VERSION 5.7 ;
  NOWIREEXTENSIONATPIN ON ;
  DIVIDERCHAR "/" ;
  BUSBITCHARS "[]" ;
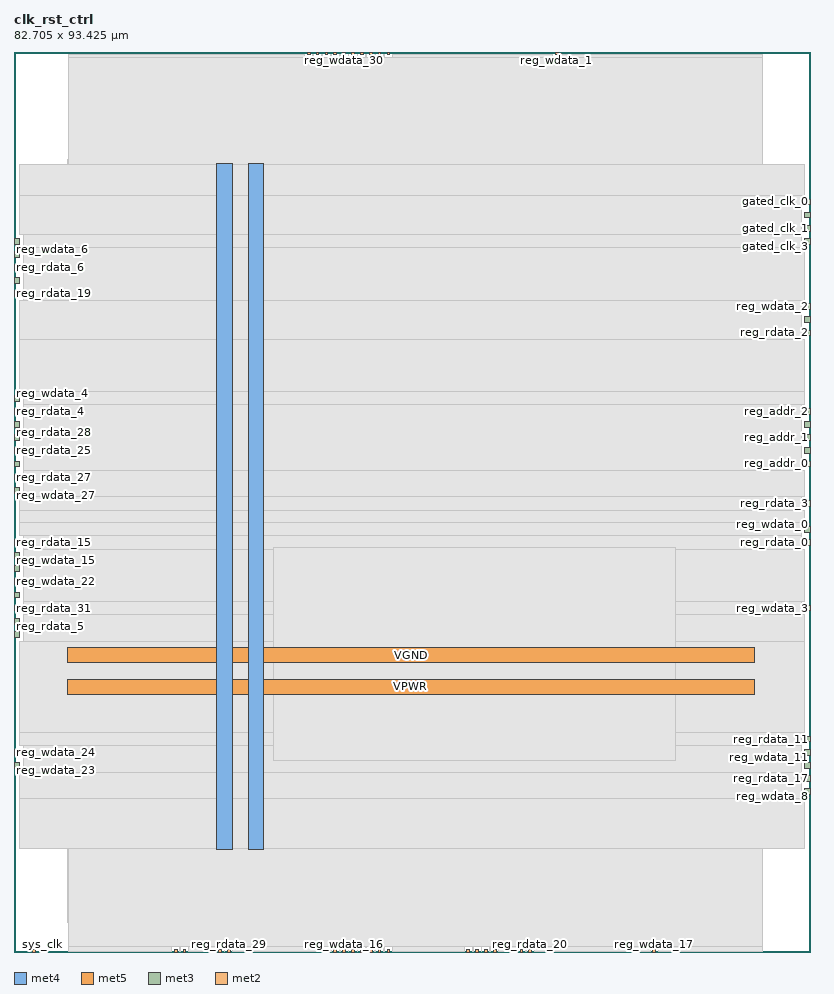
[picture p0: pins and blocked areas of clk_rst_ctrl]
MACRO clk_rst_ctrl
  CLASS BLOCK ;
  FOREIGN clk_rst_ctrl ;
  ORIGIN 0.000 0.000 ;
  SIZE 82.705 BY 93.425 ;
  PIN VGND
    DIRECTION INOUT ;
    USE GROUND ;
    PORT
      LAYER met4 ;
        RECT 24.340 10.640 25.940 81.840 ;
    END
    PORT
      LAYER met5 ;
        RECT 5.520 30.030 76.820 31.630 ;
    END
  END VGND
  PIN VPWR
    DIRECTION INOUT ;
    USE POWER ;
    PORT
      LAYER met4 ;
        RECT 21.040 10.640 22.640 81.840 ;
    END
    PORT
      LAYER met5 ;
        RECT 5.520 26.730 76.820 28.330 ;
    END
  END VPWR
  PIN gated_clk_0
    DIRECTION OUTPUT ;
    USE SIGNAL ;
    ANTENNAGATEAREA 0.434700 ;
    ANTENNADIFFAREA 0.434700 ;
    PORT
      LAYER met3 ;
        RECT 82.105 77.560 82.705 78.160 ;
    END
  END gated_clk_0
  PIN gated_clk_1
    DIRECTION OUTPUT ;
    USE SIGNAL ;
    ANTENNAGATEAREA 0.434700 ;
    ANTENNADIFFAREA 0.775300 ;
    PORT
      LAYER met3 ;
        RECT 82.105 74.840 82.705 75.440 ;
    END
  END gated_clk_1
  PIN gated_clk_2
    DIRECTION OUTPUT ;
    USE SIGNAL ;
    ANTENNAGATEAREA 0.434700 ;
    ANTENNADIFFAREA 0.775300 ;
    PORT
      LAYER met3 ;
        RECT 82.105 76.200 82.705 76.800 ;
    END
  END gated_clk_2
  PIN gated_clk_3
    DIRECTION OUTPUT ;
    USE SIGNAL ;
    ANTENNAGATEAREA 0.434700 ;
    ANTENNADIFFAREA 0.775300 ;
    PORT
      LAYER met3 ;
        RECT 82.105 73.480 82.705 74.080 ;
    END
  END gated_clk_3
  PIN reg_addr_0
    DIRECTION INPUT ;
    USE SIGNAL ;
    ANTENNAGATEAREA 0.647700 ;
    ANTENNADIFFAREA 0.434700 ;
    PORT
      LAYER met3 ;
        RECT 82.105 50.360 82.705 50.960 ;
    END
  END reg_addr_0
  PIN reg_addr_1
    DIRECTION INPUT ;
    USE SIGNAL ;
    ANTENNAGATEAREA 0.647700 ;
    ANTENNADIFFAREA 0.434700 ;
    PORT
      LAYER met3 ;
        RECT 82.105 53.080 82.705 53.680 ;
    END
  END reg_addr_1
  PIN reg_addr_2
    DIRECTION INPUT ;
    USE SIGNAL ;
    ANTENNAGATEAREA 0.647700 ;
    ANTENNADIFFAREA 0.434700 ;
    PORT
      LAYER met3 ;
        RECT 82.105 55.800 82.705 56.400 ;
    END
  END reg_addr_2
  PIN reg_addr_3
    DIRECTION INPUT ;
    USE SIGNAL ;
    ANTENNAGATEAREA 0.647700 ;
    ANTENNADIFFAREA 0.434700 ;
    PORT
      LAYER met3 ;
        RECT 82.105 51.720 82.705 52.320 ;
    END
  END reg_addr_3
  PIN reg_rd
    DIRECTION INPUT ;
    USE SIGNAL ;
    PORT
      LAYER met2 ;
        RECT 1.930 0.000 2.210 0.280 ;
    END
  END reg_rd
  PIN reg_rdata_0
    DIRECTION OUTPUT ;
    USE SIGNAL ;
    ANTENNAGATEAREA 0.434700 ;
    ANTENNADIFFAREA 1.137600 ;
    PORT
      LAYER met3 ;
        RECT 82.105 42.200 82.705 42.800 ;
    END
  END reg_rdata_0
  PIN reg_rdata_1
    DIRECTION OUTPUT ;
    USE SIGNAL ;
    ANTENNAGATEAREA 0.434700 ;
    ANTENNADIFFAREA 1.137600 ;
    PORT
      LAYER met3 ;
        RECT 82.105 65.320 82.705 65.920 ;
    END
  END reg_rdata_1
  PIN reg_rdata_10
    DIRECTION OUTPUT ;
    USE SIGNAL ;
    ANTENNAGATEAREA 0.434700 ;
    ANTENNADIFFAREA 1.137600 ;
    PORT
      LAYER met2 ;
        RECT 38.730 0.000 39.010 0.280 ;
    END
  END reg_rdata_10
  PIN reg_rdata_11
    DIRECTION OUTPUT ;
    USE SIGNAL ;
    ANTENNAGATEAREA 0.434700 ;
    ANTENNADIFFAREA 1.137600 ;
    PORT
      LAYER met3 ;
        RECT 82.105 21.800 82.705 22.400 ;
    END
  END reg_rdata_11
  PIN reg_rdata_12
    DIRECTION OUTPUT ;
    USE SIGNAL ;
    ANTENNAGATEAREA 0.434700 ;
    ANTENNADIFFAREA 1.137600 ;
    PORT
      LAYER met2 ;
        RECT 32.290 0.000 32.570 0.280 ;
    END
  END reg_rdata_12
  PIN reg_rdata_13
    DIRECTION OUTPUT ;
    USE SIGNAL ;
    ANTENNAGATEAREA 0.434700 ;
    ANTENNADIFFAREA 1.137600 ;
    PORT
      LAYER met2 ;
        RECT 31.370 93.145 31.650 93.425 ;
    END
  END reg_rdata_13
  PIN reg_rdata_14
    DIRECTION OUTPUT ;
    USE SIGNAL ;
    ANTENNAGATEAREA 0.434700 ;
    ANTENNADIFFAREA 1.137600 ;
    PORT
      LAYER met2 ;
        RECT 33.210 93.145 33.490 93.425 ;
    END
  END reg_rdata_14
  PIN reg_rdata_15
    DIRECTION OUTPUT ;
    USE SIGNAL ;
    ANTENNAGATEAREA 0.434700 ;
    ANTENNADIFFAREA 1.137600 ;
    PORT
      LAYER met3 ;
        RECT 0.000 42.200 0.600 42.800 ;
    END
  END reg_rdata_15
  PIN reg_rdata_16
    DIRECTION OUTPUT ;
    USE SIGNAL ;
    ANTENNAGATEAREA 0.434700 ;
    ANTENNADIFFAREA 1.137600 ;
    PORT
      LAYER met2 ;
        RECT 35.970 0.000 36.250 0.280 ;
    END
  END reg_rdata_16
  PIN reg_rdata_17
    DIRECTION OUTPUT ;
    USE SIGNAL ;
    ANTENNAGATEAREA 0.434700 ;
    ANTENNADIFFAREA 1.137600 ;
    PORT
      LAYER met3 ;
        RECT 82.105 17.720 82.705 18.320 ;
    END
  END reg_rdata_17
  PIN reg_rdata_18
    DIRECTION OUTPUT ;
    USE SIGNAL ;
    ANTENNAGATEAREA 0.434700 ;
    ANTENNADIFFAREA 1.137600 ;
    PORT
      LAYER met2 ;
        RECT 38.730 93.145 39.010 93.425 ;
    END
  END reg_rdata_18
  PIN reg_rdata_19
    DIRECTION OUTPUT ;
    USE SIGNAL ;
    ANTENNAGATEAREA 0.434700 ;
    ANTENNADIFFAREA 1.137600 ;
    PORT
      LAYER met3 ;
        RECT 0.000 68.040 0.600 68.640 ;
    END
  END reg_rdata_19
  PIN reg_rdata_2
    DIRECTION OUTPUT ;
    USE SIGNAL ;
    ANTENNAGATEAREA 0.434700 ;
    ANTENNADIFFAREA 1.137600 ;
    PORT
      LAYER met3 ;
        RECT 82.105 63.960 82.705 64.560 ;
    END
  END reg_rdata_2
  PIN reg_rdata_20
    DIRECTION OUTPUT ;
    USE SIGNAL ;
    ANTENNAGATEAREA 0.434700 ;
    ANTENNADIFFAREA 1.137600 ;
    PORT
      LAYER met2 ;
        RECT 53.450 0.000 53.730 0.280 ;
    END
  END reg_rdata_20
  PIN reg_rdata_21
    DIRECTION OUTPUT ;
    USE SIGNAL ;
    ANTENNAGATEAREA 0.434700 ;
    ANTENNADIFFAREA 1.137600 ;
    PORT
      LAYER met2 ;
        RECT 36.890 93.145 37.170 93.425 ;
    END
  END reg_rdata_21
  PIN reg_rdata_22
    DIRECTION OUTPUT ;
    USE SIGNAL ;
    ANTENNAGATEAREA 0.434700 ;
    ANTENNADIFFAREA 1.137600 ;
    PORT
      LAYER met3 ;
        RECT 0.000 39.480 0.600 40.080 ;
    END
  END reg_rdata_22
  PIN reg_rdata_23
    DIRECTION OUTPUT ;
    USE SIGNAL ;
    ANTENNAGATEAREA 0.434700 ;
    ANTENNADIFFAREA 1.137600 ;
    PORT
      LAYER met2 ;
        RECT 17.570 0.000 17.850 0.280 ;
    END
  END reg_rdata_23
  PIN reg_rdata_24
    DIRECTION OUTPUT ;
    USE SIGNAL ;
    ANTENNAGATEAREA 0.434700 ;
    ANTENNADIFFAREA 1.137600 ;
    PORT
      LAYER met2 ;
        RECT 16.650 0.000 16.930 0.280 ;
    END
  END reg_rdata_24
  PIN reg_rdata_25
    DIRECTION OUTPUT ;
    USE SIGNAL ;
    ANTENNAGATEAREA 0.434700 ;
    ANTENNADIFFAREA 1.137600 ;
    PORT
      LAYER met3 ;
        RECT 0.000 51.720 0.600 52.320 ;
    END
  END reg_rdata_25
  PIN reg_rdata_26
    DIRECTION OUTPUT ;
    USE SIGNAL ;
    ANTENNAGATEAREA 0.434700 ;
    ANTENNADIFFAREA 1.137600 ;
    PORT
      LAYER met2 ;
        RECT 49.770 0.000 50.050 0.280 ;
    END
  END reg_rdata_26
  PIN reg_rdata_27
    DIRECTION OUTPUT ;
    USE SIGNAL ;
    ANTENNAGATEAREA 0.434700 ;
    ANTENNADIFFAREA 1.137600 ;
    PORT
      LAYER met3 ;
        RECT 0.000 49.000 0.600 49.600 ;
    END
  END reg_rdata_27
  PIN reg_rdata_28
    DIRECTION OUTPUT ;
    USE SIGNAL ;
    ANTENNAGATEAREA 0.434700 ;
    ANTENNADIFFAREA 1.137600 ;
    PORT
      LAYER met3 ;
        RECT 0.000 53.080 0.600 53.680 ;
    END
  END reg_rdata_28
  PIN reg_rdata_29
    DIRECTION OUTPUT ;
    USE SIGNAL ;
    ANTENNAGATEAREA 0.434700 ;
    ANTENNADIFFAREA 1.137600 ;
    PORT
      LAYER met2 ;
        RECT 22.170 0.000 22.450 0.280 ;
    END
  END reg_rdata_29
  PIN reg_rdata_3
    DIRECTION OUTPUT ;
    USE SIGNAL ;
    ANTENNAGATEAREA 0.434700 ;
    ANTENNADIFFAREA 1.137600 ;
    PORT
      LAYER met3 ;
        RECT 82.105 46.280 82.705 46.880 ;
    END
  END reg_rdata_3
  PIN reg_rdata_30
    DIRECTION OUTPUT ;
    USE SIGNAL ;
    ANTENNAGATEAREA 0.434700 ;
    ANTENNADIFFAREA 1.137600 ;
    PORT
      LAYER met2 ;
        RECT 35.970 93.145 36.250 93.425 ;
    END
  END reg_rdata_30
  PIN reg_rdata_31
    DIRECTION OUTPUT ;
    USE SIGNAL ;
    ANTENNAGATEAREA 0.434700 ;
    ANTENNADIFFAREA 1.137600 ;
    PORT
      LAYER met3 ;
        RECT 0.000 35.400 0.600 36.000 ;
    END
  END reg_rdata_31
  PIN reg_rdata_4
    DIRECTION OUTPUT ;
    USE SIGNAL ;
    ANTENNAGATEAREA 0.434700 ;
    ANTENNADIFFAREA 1.137600 ;
    PORT
      LAYER met3 ;
        RECT 0.000 55.800 0.600 56.400 ;
    END
  END reg_rdata_4
  PIN reg_rdata_5
    DIRECTION OUTPUT ;
    USE SIGNAL ;
    ANTENNAGATEAREA 0.434700 ;
    ANTENNADIFFAREA 1.137600 ;
    PORT
      LAYER met3 ;
        RECT 0.000 34.040 0.600 34.640 ;
    END
  END reg_rdata_5
  PIN reg_rdata_6
    DIRECTION OUTPUT ;
    USE SIGNAL ;
    ANTENNAGATEAREA 0.434700 ;
    ANTENNADIFFAREA 1.137600 ;
    PORT
      LAYER met3 ;
        RECT 0.000 70.760 0.600 71.360 ;
    END
  END reg_rdata_6
  PIN reg_rdata_7
    DIRECTION OUTPUT ;
    USE SIGNAL ;
    ANTENNAGATEAREA 0.434700 ;
    ANTENNADIFFAREA 1.137600 ;
    PORT
      LAYER met2 ;
        RECT 47.930 0.000 48.210 0.280 ;
    END
  END reg_rdata_7
  PIN reg_rdata_8
    DIRECTION OUTPUT ;
    USE SIGNAL ;
    ANTENNAGATEAREA 0.434700 ;
    ANTENNADIFFAREA 1.137600 ;
    PORT
      LAYER met3 ;
        RECT 82.105 19.080 82.705 19.680 ;
    END
  END reg_rdata_8
  PIN reg_rdata_9
    DIRECTION OUTPUT ;
    USE SIGNAL ;
    ANTENNAGATEAREA 0.434700 ;
    ANTENNADIFFAREA 1.137600 ;
    PORT
      LAYER met2 ;
        RECT 37.810 0.000 38.090 0.280 ;
    END
  END reg_rdata_9
  PIN reg_wdata_0
    DIRECTION INPUT ;
    USE SIGNAL ;
    ANTENNAGATEAREA 0.647700 ;
    ANTENNADIFFAREA 0.434700 ;
    PORT
      LAYER met3 ;
        RECT 82.105 43.560 82.705 44.160 ;
    END
  END reg_wdata_0
  PIN reg_wdata_1
    DIRECTION INPUT ;
    USE SIGNAL ;
    ANTENNAGATEAREA 0.647700 ;
    ANTENNADIFFAREA 0.434700 ;
    PORT
      LAYER met2 ;
        RECT 56.210 93.145 56.490 93.425 ;
    END
  END reg_wdata_1
  PIN reg_wdata_10
    DIRECTION INPUT ;
    USE SIGNAL ;
    ANTENNAGATEAREA 0.647700 ;
    ANTENNADIFFAREA 0.434700 ;
    PORT
      LAYER met2 ;
        RECT 35.050 0.000 35.330 0.280 ;
    END
  END reg_wdata_10
  PIN reg_wdata_11
    DIRECTION INPUT ;
    USE SIGNAL ;
    ANTENNAGATEAREA 0.647700 ;
    ANTENNADIFFAREA 0.434700 ;
    PORT
      LAYER met3 ;
        RECT 82.105 20.440 82.705 21.040 ;
    END
  END reg_wdata_11
  PIN reg_wdata_12
    DIRECTION INPUT ;
    USE SIGNAL ;
    ANTENNAGATEAREA 0.647700 ;
    ANTENNADIFFAREA 0.434700 ;
    PORT
      LAYER met2 ;
        RECT 33.210 0.000 33.490 0.280 ;
    END
  END reg_wdata_12
  PIN reg_wdata_13
    DIRECTION INPUT ;
    USE SIGNAL ;
    ANTENNAGATEAREA 0.647700 ;
    ANTENNADIFFAREA 0.434700 ;
    PORT
      LAYER met2 ;
        RECT 30.450 93.145 30.730 93.425 ;
    END
  END reg_wdata_13
  PIN reg_wdata_14
    DIRECTION INPUT ;
    USE SIGNAL ;
    ANTENNAGATEAREA 0.647700 ;
    ANTENNADIFFAREA 0.434700 ;
    PORT
      LAYER met2 ;
        RECT 32.290 93.145 32.570 93.425 ;
    END
  END reg_wdata_14
  PIN reg_wdata_15
    DIRECTION INPUT ;
    USE SIGNAL ;
    ANTENNAGATEAREA 0.647700 ;
    ANTENNADIFFAREA 0.434700 ;
    PORT
      LAYER met3 ;
        RECT 0.000 40.840 0.600 41.440 ;
    END
  END reg_wdata_15
  PIN reg_wdata_16
    DIRECTION INPUT ;
    USE SIGNAL ;
    ANTENNAGATEAREA 0.647700 ;
    ANTENNADIFFAREA 0.434700 ;
    PORT
      LAYER met2 ;
        RECT 34.130 0.000 34.410 0.280 ;
    END
  END reg_wdata_16
  PIN reg_wdata_17
    DIRECTION INPUT ;
    USE SIGNAL ;
    ANTENNAGATEAREA 0.647700 ;
    ANTENNADIFFAREA 0.434700 ;
    PORT
      LAYER met2 ;
        RECT 66.330 0.000 66.610 0.280 ;
    END
  END reg_wdata_17
  PIN reg_wdata_18
    DIRECTION INPUT ;
    USE SIGNAL ;
    ANTENNAGATEAREA 0.647700 ;
    ANTENNADIFFAREA 0.434700 ;
    PORT
      LAYER met2 ;
        RECT 37.810 93.145 38.090 93.425 ;
    END
  END reg_wdata_18
  PIN reg_wdata_19
    DIRECTION INPUT ;
    USE SIGNAL ;
    ANTENNAGATEAREA 0.647700 ;
    ANTENNADIFFAREA 0.434700 ;
    PORT
      LAYER met3 ;
        RECT 0.000 69.400 0.600 70.000 ;
    END
  END reg_wdata_19
  PIN reg_wdata_2
    DIRECTION INPUT ;
    USE SIGNAL ;
    ANTENNAGATEAREA 0.647700 ;
    ANTENNADIFFAREA 0.434700 ;
    PORT
      LAYER met3 ;
        RECT 82.105 66.680 82.705 67.280 ;
    END
  END reg_wdata_2
  PIN reg_wdata_20
    DIRECTION INPUT ;
    USE SIGNAL ;
    ANTENNAGATEAREA 0.647700 ;
    ANTENNADIFFAREA 0.434700 ;
    PORT
      LAYER met2 ;
        RECT 52.530 0.000 52.810 0.280 ;
    END
  END reg_wdata_20
  PIN reg_wdata_21
    DIRECTION INPUT ;
    USE SIGNAL ;
    ANTENNAGATEAREA 0.647700 ;
    ANTENNADIFFAREA 0.434700 ;
    PORT
      LAYER met2 ;
        RECT 35.050 93.145 35.330 93.425 ;
    END
  END reg_wdata_21
  PIN reg_wdata_22
    DIRECTION INPUT ;
    USE SIGNAL ;
    ANTENNAGATEAREA 0.647700 ;
    ANTENNADIFFAREA 0.434700 ;
    PORT
      LAYER met3 ;
        RECT 0.000 38.120 0.600 38.720 ;
    END
  END reg_wdata_22
  PIN reg_wdata_23
    DIRECTION INPUT ;
    USE SIGNAL ;
    ANTENNAGATEAREA 0.647700 ;
    ANTENNADIFFAREA 0.434700 ;
    PORT
      LAYER met3 ;
        RECT 0.000 19.080 0.600 19.680 ;
    END
  END reg_wdata_23
  PIN reg_wdata_24
    DIRECTION INPUT ;
    USE SIGNAL ;
    ANTENNAGATEAREA 0.647700 ;
    ANTENNADIFFAREA 0.434700 ;
    PORT
      LAYER met3 ;
        RECT 0.000 20.440 0.600 21.040 ;
    END
  END reg_wdata_24
  PIN reg_wdata_25
    DIRECTION INPUT ;
    USE SIGNAL ;
    ANTENNAGATEAREA 0.647700 ;
    ANTENNADIFFAREA 0.434700 ;
    PORT
      LAYER met3 ;
        RECT 0.000 50.360 0.600 50.960 ;
    END
  END reg_wdata_25
  PIN reg_wdata_26
    DIRECTION INPUT ;
    USE SIGNAL ;
    ANTENNAGATEAREA 0.647700 ;
    ANTENNADIFFAREA 0.434700 ;
    PORT
      LAYER met2 ;
        RECT 48.850 0.000 49.130 0.280 ;
    END
  END reg_wdata_26
  PIN reg_wdata_27
    DIRECTION INPUT ;
    USE SIGNAL ;
    ANTENNAGATEAREA 0.647700 ;
    ANTENNADIFFAREA 0.434700 ;
    PORT
      LAYER met3 ;
        RECT 0.000 47.640 0.600 48.240 ;
    END
  END reg_wdata_27
  PIN reg_wdata_28
    DIRECTION INPUT ;
    USE SIGNAL ;
    ANTENNAGATEAREA 0.647700 ;
    ANTENNADIFFAREA 0.434700 ;
    PORT
      LAYER met3 ;
        RECT 0.000 54.440 0.600 55.040 ;
    END
  END reg_wdata_28
  PIN reg_wdata_29
    DIRECTION INPUT ;
    USE SIGNAL ;
    ANTENNAGATEAREA 0.647700 ;
    ANTENNADIFFAREA 0.434700 ;
    PORT
      LAYER met2 ;
        RECT 21.250 0.000 21.530 0.280 ;
    END
  END reg_wdata_29
  PIN reg_wdata_3
    DIRECTION INPUT ;
    USE SIGNAL ;
    ANTENNAGATEAREA 0.647700 ;
    ANTENNADIFFAREA 0.434700 ;
    PORT
      LAYER met3 ;
        RECT 82.105 35.400 82.705 36.000 ;
    END
  END reg_wdata_3
  PIN reg_wdata_30
    DIRECTION INPUT ;
    USE SIGNAL ;
    ANTENNAGATEAREA 0.647700 ;
    ANTENNADIFFAREA 0.434700 ;
    PORT
      LAYER met2 ;
        RECT 34.130 93.145 34.410 93.425 ;
    END
  END reg_wdata_30
  PIN reg_wdata_31
    DIRECTION INPUT ;
    USE SIGNAL ;
    ANTENNAGATEAREA 0.647700 ;
    ANTENNADIFFAREA 0.434700 ;
    PORT
      LAYER met3 ;
        RECT 0.000 36.760 0.600 37.360 ;
    END
  END reg_wdata_31
  PIN reg_wdata_4
    DIRECTION INPUT ;
    USE SIGNAL ;
    ANTENNAGATEAREA 0.647700 ;
    ANTENNADIFFAREA 0.434700 ;
    PORT
      LAYER met3 ;
        RECT 0.000 57.160 0.600 57.760 ;
    END
  END reg_wdata_4
  PIN reg_wdata_5
    DIRECTION INPUT ;
    USE SIGNAL ;
    ANTENNAGATEAREA 0.647700 ;
    ANTENNADIFFAREA 0.434700 ;
    PORT
      LAYER met3 ;
        RECT 0.000 32.680 0.600 33.280 ;
    END
  END reg_wdata_5
  PIN reg_wdata_6
    DIRECTION INPUT ;
    USE SIGNAL ;
    ANTENNAGATEAREA 0.647700 ;
    ANTENNADIFFAREA 0.434700 ;
    PORT
      LAYER met3 ;
        RECT 0.000 72.120 0.600 72.720 ;
    END
  END reg_wdata_6
  PIN reg_wdata_7
    DIRECTION INPUT ;
    USE SIGNAL ;
    ANTENNAGATEAREA 0.647700 ;
    ANTENNADIFFAREA 0.434700 ;
    PORT
      LAYER met2 ;
        RECT 47.010 0.000 47.290 0.280 ;
    END
  END reg_wdata_7
  PIN reg_wdata_8
    DIRECTION INPUT ;
    USE SIGNAL ;
    ANTENNAGATEAREA 0.647700 ;
    ANTENNADIFFAREA 0.434700 ;
    PORT
      LAYER met3 ;
        RECT 82.105 16.360 82.705 16.960 ;
    END
  END reg_wdata_8
  PIN reg_wdata_9
    DIRECTION INPUT ;
    USE SIGNAL ;
    ANTENNAGATEAREA 0.647700 ;
    ANTENNADIFFAREA 0.434700 ;
    PORT
      LAYER met2 ;
        RECT 36.890 0.000 37.170 0.280 ;
    END
  END reg_wdata_9
  PIN reg_wr
    DIRECTION INPUT ;
    USE SIGNAL ;
    ANTENNAGATEAREA 0.647700 ;
    ANTENNADIFFAREA 0.434700 ;
    PORT
      LAYER met3 ;
        RECT 82.105 54.440 82.705 55.040 ;
    END
  END reg_wr
  PIN sys_clk
    DIRECTION OUTPUT ;
    USE SIGNAL ;
    PORT
      LAYER met2 ;
        RECT 2.850 0.000 3.130 0.280 ;
    END
  END sys_clk
  PIN sys_rst_n
    DIRECTION OUTPUT ;
    USE SIGNAL ;
    ANTENNAGATEAREA 0.434700 ;
    ANTENNADIFFAREA 1.137600 ;
    PORT
      LAYER met3 ;
        RECT 0.000 73.480 0.600 74.080 ;
    END
  END sys_rst_n
  OBS
      LAYER nwell ;
        RECT 5.330 10.795 77.010 81.685 ;
      LAYER li1 ;
        RECT 5.520 10.795 76.820 81.685 ;
      LAYER met1 ;
        RECT 5.520 3.100 77.670 82.240 ;
      LAYER met2 ;
        RECT 5.610 92.865 30.170 93.145 ;
        RECT 31.010 92.865 31.090 93.145 ;
        RECT 31.930 92.865 32.010 93.145 ;
        RECT 32.850 92.865 32.930 93.145 ;
        RECT 33.770 92.865 33.850 93.145 ;
        RECT 34.690 92.865 34.770 93.145 ;
        RECT 35.610 92.865 35.690 93.145 ;
        RECT 36.530 92.865 36.610 93.145 ;
        RECT 37.450 92.865 37.530 93.145 ;
        RECT 38.370 92.865 38.450 93.145 ;
        RECT 39.290 92.865 55.930 93.145 ;
        RECT 56.770 92.865 77.650 93.145 ;
        RECT 5.610 0.560 77.650 92.865 ;
        RECT 5.610 0.070 16.370 0.560 ;
        RECT 17.210 0.070 17.290 0.560 ;
        RECT 18.130 0.070 20.970 0.560 ;
        RECT 21.810 0.070 21.890 0.560 ;
        RECT 22.730 0.070 32.010 0.560 ;
        RECT 32.850 0.070 32.930 0.560 ;
        RECT 33.770 0.070 33.850 0.560 ;
        RECT 34.690 0.070 34.770 0.560 ;
        RECT 35.610 0.070 35.690 0.560 ;
        RECT 36.530 0.070 36.610 0.560 ;
        RECT 37.450 0.070 37.530 0.560 ;
        RECT 38.370 0.070 38.450 0.560 ;
        RECT 39.290 0.070 46.730 0.560 ;
        RECT 47.570 0.070 47.650 0.560 ;
        RECT 48.490 0.070 48.570 0.560 ;
        RECT 49.410 0.070 49.490 0.560 ;
        RECT 50.330 0.070 52.250 0.560 ;
        RECT 53.090 0.070 53.170 0.560 ;
        RECT 54.010 0.070 66.050 0.560 ;
        RECT 66.890 0.070 77.650 0.560 ;
      LAYER met3 ;
        RECT 0.600 78.560 82.105 81.765 ;
        RECT 0.600 74.480 81.705 78.560 ;
        RECT 1.000 73.080 81.705 74.480 ;
        RECT 1.000 67.680 82.105 73.080 ;
        RECT 1.000 67.640 81.705 67.680 ;
        RECT 0.600 63.560 81.705 67.640 ;
        RECT 0.600 58.160 82.105 63.560 ;
        RECT 1.000 56.800 82.105 58.160 ;
        RECT 1.000 49.960 81.705 56.800 ;
        RECT 1.000 47.280 82.105 49.960 ;
        RECT 1.000 47.240 81.705 47.280 ;
        RECT 0.600 45.880 81.705 47.240 ;
        RECT 0.600 44.560 82.105 45.880 ;
        RECT 0.600 43.200 81.705 44.560 ;
        RECT 1.000 41.800 81.705 43.200 ;
        RECT 1.000 36.400 82.105 41.800 ;
        RECT 1.000 35.000 81.705 36.400 ;
        RECT 1.000 32.280 82.105 35.000 ;
        RECT 0.600 22.800 82.105 32.280 ;
        RECT 0.600 21.440 81.705 22.800 ;
        RECT 1.000 18.680 81.705 21.440 ;
        RECT 0.600 15.960 81.705 18.680 ;
        RECT 0.600 10.715 82.105 15.960 ;
      LAYER met4 ;
        RECT 26.975 19.895 68.705 41.985 ;
  END
END clk_rst_ctrl
END LIBRARY

